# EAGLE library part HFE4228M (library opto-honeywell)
OPTO SENSOR DEVICE

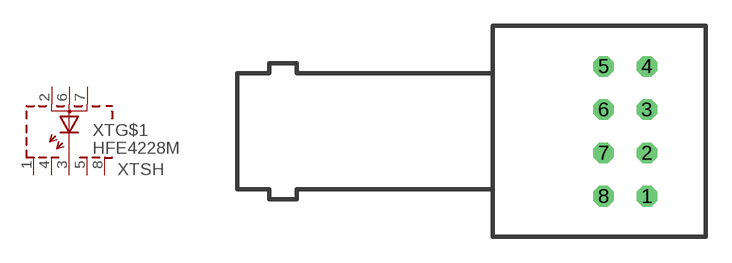
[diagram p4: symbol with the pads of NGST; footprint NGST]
Designator prefix XT; gates G$1=LED-A3 SH=CASE4COM

## HFE4228M (OC_FARNELL: unknown; OC_NEWARK: unknown)  [NGST]
1  SH:COM  pwr
2  G$1:A1  pas
3  G$1:C  pas
4  SH:COM  pwr
5  SH:COM  pwr
6  G$1:A2  pas
7  G$1:A3  pas
8  SH:COM  pwr

## Footprint NGST (pad centres in mm)
OPTO SENSOR DEVICE
drill 0.7 octagon: 1 2.54,-3.81; 2 2.54,-1.27; 3 2.54,1.27; 4 2.54,3.81; 5 0,3.81; 6 0,1.27; 7 0,-1.27; 8 0,-3.81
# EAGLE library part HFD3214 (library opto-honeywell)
OPTO SENSOR DEVICE

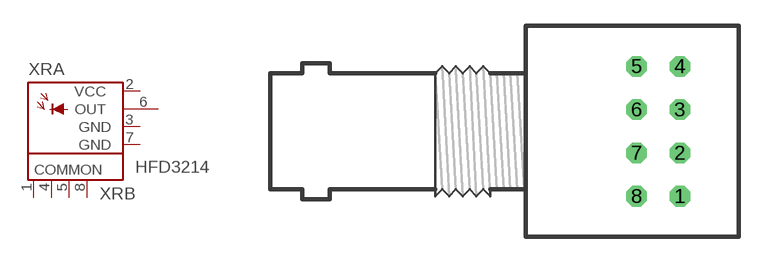
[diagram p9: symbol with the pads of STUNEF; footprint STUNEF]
Designator prefix XR; gates A=DETECT2G B=COMMON4

## HFD3214 (OC_FARNELL: unknown; OC_NEWARK: unknown)  [STUNEF]
1  B:COM  pwr
2  A:VCC  pwr
3  A:GND  pwr
4  B:COM  pwr
5  B:COM  pwr
6  A:OUT  out
7  A:GND  pwr
8  B:COM  pwr

## Footprint STUNEF (pad centres in mm)
OPTO SENSOR DEVICE
drill 0.7 octagon: 1 2.54,-3.81; 2 2.54,-1.27; 3 2.54,1.27; 4 2.54,3.81; 5 0,3.81; 6 0,1.27; 7 0,-1.27; 8 0,-3.81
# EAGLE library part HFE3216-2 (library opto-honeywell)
OPTO SENSOR DEVICE

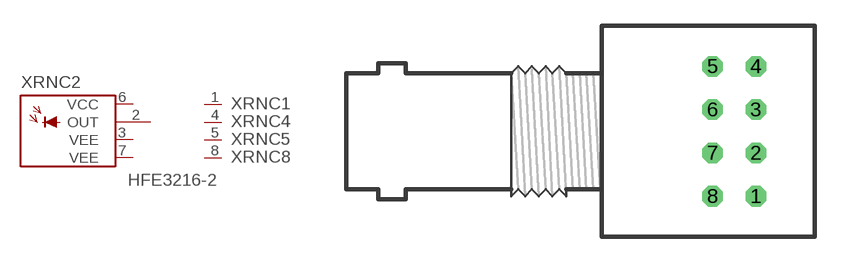
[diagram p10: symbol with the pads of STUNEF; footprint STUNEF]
Designator prefix XR; gates NC1=NC NC4=NC NC5=NC NC8=NC NC2=DET-CCEE

## HFE3216-2 (OC_FARNELL: unknown; OC_NEWARK: unknown)  [STUNEF]
1  NC1:NC  nc
2  NC2:OUT  out
3  NC2:VEE  pwr
4  NC4:NC  nc
5  NC5:NC  nc
6  NC2:VCC  pwr
7  NC2:VEE  pwr
8  NC8:NC  nc

## Footprint STUNEF (pad centres in mm)
OPTO SENSOR DEVICE
drill 0.7 octagon: 1 2.54,-3.81; 2 2.54,-1.27; 3 2.54,1.27; 4 2.54,3.81; 5 0,3.81; 6 0,1.27; 7 0,-1.27; 8 0,-3.81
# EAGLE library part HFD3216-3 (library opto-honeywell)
OPTO SENSOR DEVICE

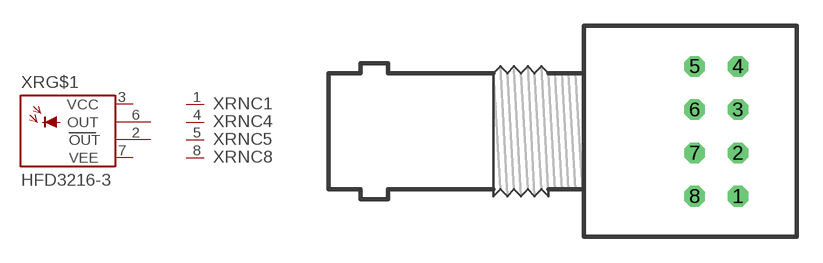
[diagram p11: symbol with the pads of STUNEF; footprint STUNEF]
Designator prefix XR; gates G$1=DETNCCEE NC1=NC NC4=NC NC5=NC NC8=NC

## HFD3216-3 (OC_FARNELL: unknown; OC_NEWARK: unknown)  [STUNEF]
1  NC1:NC  nc
2  G$1:!OUT  out
3  G$1:VCC  pwr
4  NC4:NC  nc
5  NC5:NC  nc
6  G$1:OUT  out
7  G$1:VEE  pwr
8  NC8:NC  nc

## Footprint STUNEF (pad centres in mm)
OPTO SENSOR DEVICE
drill 0.7 octagon: 1 2.54,-3.81; 2 2.54,-1.27; 3 2.54,1.27; 4 2.54,3.81; 5 0,3.81; 6 0,1.27; 7 0,-1.27; 8 0,-3.81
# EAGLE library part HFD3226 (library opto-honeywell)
OPTO SENSOR DEVICE

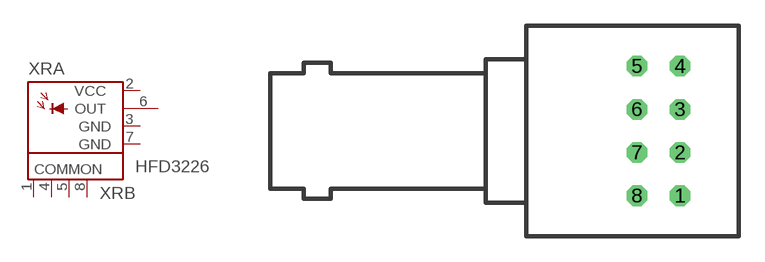
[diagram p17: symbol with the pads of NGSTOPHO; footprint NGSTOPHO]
Designator prefix XR; gates A=DETECT2G B=COMMON4

## HFD3226 (OC_FARNELL: unknown; OC_NEWARK: unknown)  [NGSTOPHO]
1  B:COM  pwr
2  A:VCC  pwr
3  A:GND  pwr
4  B:COM  pwr
5  B:COM  pwr
6  A:OUT  out
7  A:GND  pwr
8  B:COM  pwr

## Footprint NGSTOPHO (pad centres in mm)
OPTO SENSOR DEVICE
drill 0.7 octagon: 1 2.54,-3.81; 2 2.54,-1.27; 3 2.54,1.27; 4 2.54,3.81; 5 0,3.81; 6 0,1.27; 7 0,-1.27; 8 0,-3.81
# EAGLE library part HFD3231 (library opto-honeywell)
OPTO SENSOR DEVICE

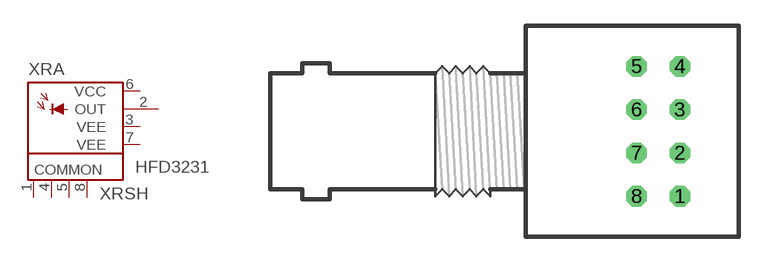
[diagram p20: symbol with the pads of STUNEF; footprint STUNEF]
Designator prefix XR; gates A=DET-CCEE SH=COMMON4

## HFD3231 (OC_FARNELL: unknown; OC_NEWARK: unknown)  [STUNEF]
1  SH:COM  pwr
2  A:OUT  out
3  A:VEE  pwr
4  SH:COM  pwr
5  SH:COM  pwr
6  A:VCC  pwr
7  A:VEE  pwr
8  SH:COM  pwr

## Footprint STUNEF (pad centres in mm)
OPTO SENSOR DEVICE
drill 0.7 octagon: 1 2.54,-3.81; 2 2.54,-1.27; 3 2.54,1.27; 4 2.54,3.81; 5 0,3.81; 6 0,1.27; 7 0,-1.27; 8 0,-3.81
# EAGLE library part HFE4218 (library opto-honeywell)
OPTO SENSOR DEVICE

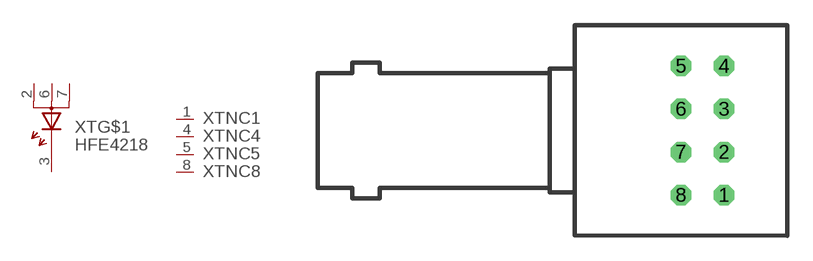
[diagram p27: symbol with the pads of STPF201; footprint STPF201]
Designator prefix XT; gates NC1=NC NC4=NC NC5=NC NC8=NC G$1=LED-A3

## HFE4218 (OC_FARNELL: unknown; OC_NEWARK: unknown)  [STPF201]
1  NC1:NC  nc
2  G$1:A1  pas
3  G$1:C  pas
4  NC4:NC  nc
5  NC5:NC  nc
6  G$1:A2  pas
7  G$1:A3  pas
8  NC8:NC  nc

## Footprint STPF201 (pad centres in mm)
OPTO SENSOR DEVICE
drill 0.7 octagon: 1 2.54,-3.81; 2 2.54,-1.27; 3 2.54,1.27; 4 2.54,3.81; 5 0,3.81; 6 0,1.27; 7 0,-1.27; 8 0,-3.81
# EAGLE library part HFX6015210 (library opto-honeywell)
OPTO SENSOR DEVICE

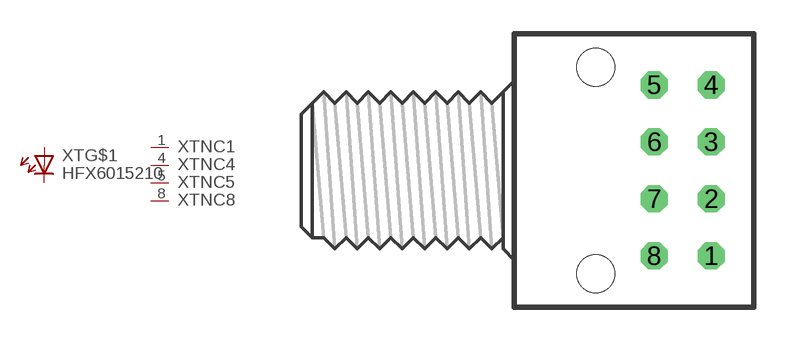
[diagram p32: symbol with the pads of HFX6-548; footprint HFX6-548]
Designator prefix XT; gates G$1=LED NC1=NC NC4=NC NC5=NC NC8=NC

## HFX6015210 (OC_FARNELL: unknown; OC_NEWARK: unknown)  [HFX6-548]
1  NC1:NC  nc
2  G$1:A  pas
3  G$1:C  pas
4  NC4:NC  nc
5  NC5:NC  nc
8  NC8:NC  nc

## Footprint HFX6-548 (pad centres in mm)
OPTO SENSOR DEVICE
drill 0.7 octagon: 1 1.27,-3.81; 2 1.27,-1.27; 3 1.27,1.27; 4 1.27,3.81; 5 -1.27,3.81; 6 -1.27,1.27; 7 -1.27,-1.27; 8 -1.27,-3.81
hole 1.7 at -3.87,-4.6
hole 1.7 at -3.87,4.6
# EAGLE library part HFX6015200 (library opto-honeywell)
OPTO SENSOR DEVICE

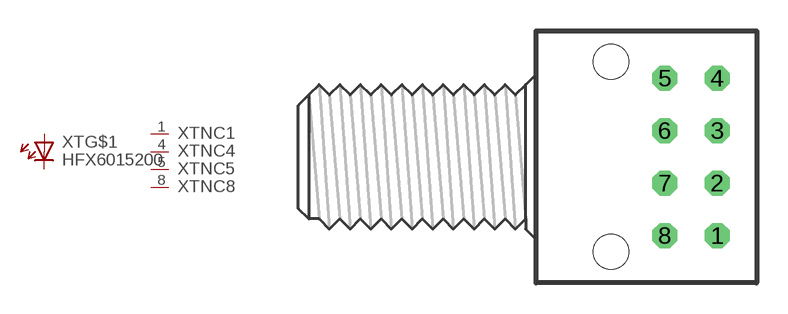
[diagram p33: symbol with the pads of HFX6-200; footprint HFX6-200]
Designator prefix XT; gates NC1=NC NC4=NC NC5=NC NC8=NC G$1=LED

## HFX6015200 (MPN: HFX6015-200; OC_FARNELL: unknown; OC_NEWARK: 34M4550)  [HFX6-200]
1  NC1:NC  nc
2  G$1:A  pas
3  G$1:C  pas
4  NC4:NC  nc
5  NC5:NC  nc
8  NC8:NC  nc

## Footprint HFX6-200 (pad centres in mm)
OPTO SENSOR DEVICE
drill 0.7 octagon: 1 1.27,-3.81; 2 1.27,-1.27; 3 1.27,1.27; 4 1.27,3.81; 5 -1.27,3.81; 6 -1.27,1.27; 7 -1.27,-1.27; 8 -1.27,-3.81
hole 1.7 at -3.87,-4.6
hole 1.7 at -3.87,4.6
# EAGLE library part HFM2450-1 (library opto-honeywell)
OPTO SENSOR DEVICE

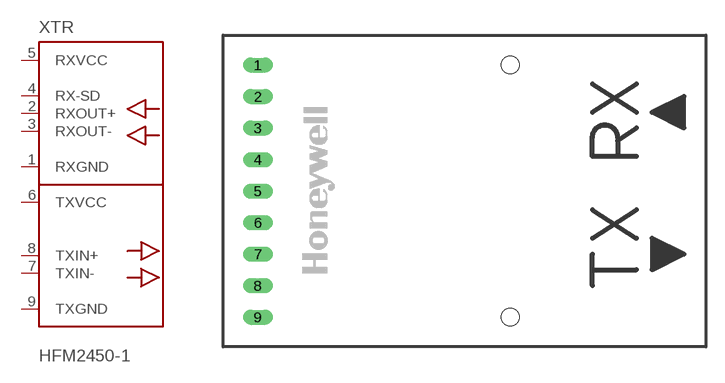
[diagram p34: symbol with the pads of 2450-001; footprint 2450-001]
Designator prefix XTR

## HFM2450-1 (OC_FARNELL: unknown; OC_NEWARK: unknown)  [2450-001]
1  RXGND  pwr
2  RXOUT+  out
3  RXOUT-  out
4  RX-SD  out
5  RXVCC  out
6  TXVCC  out
7  TXIN-  out
8  TXIN+  out
9  TXGND  pwr

## Footprint 2450-001 (pad centres in mm)
OPTO SENSOR DEVICE
drill 0.7 long: 1 -15.24,10.16; 2 -15.24,7.62; 3 -15.24,5.08; 4 -15.24,2.54; 5 -15.24,0; 6 -15.24,-2.54; 7 -15.24,-5.08; 8 -15.24,-7.62; 9 -15.24,-10.16
hole 1.422 at 5.08,10.16
hole 1.422 at 5.08,-10.16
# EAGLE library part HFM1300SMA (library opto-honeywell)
OPTO SENSOR DEVICE

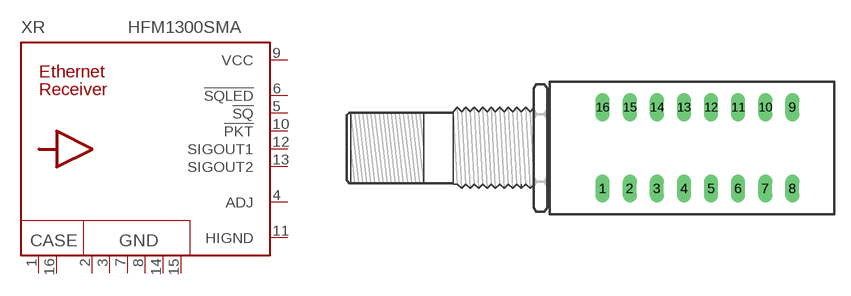
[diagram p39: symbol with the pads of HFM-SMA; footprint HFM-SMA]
Designator prefix XR

## HFM1300SMA (OC_FARNELL: unknown; OC_NEWARK: unknown)  [HFM-SMA]
1  CASEGND  pwr
2  GND  pwr
3  GND  pwr
4  ADJ  in
5  !SQ  out
6  !SQLED  out
7  GND  pwr
8  GND  pwr
9  VCC  pwr
10  !PKT  out
11  HIGND  pwr
12  SIGOUT1  out
13  SIGOUT2  out
14  GND  pwr
15  GND  pwr
16  CASEGND  pwr

## Footprint HFM-SMA (pad centres in mm)
OPTO SENSOR DEVICE
drill 0.813 long: 1 -8.89,-3.81; 2 -6.35,-3.81; 3 -3.81,-3.81; 4 -1.27,-3.81; 5 1.27,-3.81; 6 3.81,-3.81; 7 6.35,-3.81; 8 8.89,-3.81; 9 8.89,3.81; 10 6.35,3.81; 11 3.81,3.81; 12 1.27,3.81; 13 -1.27,3.81; 14 -3.81,3.81; 15 -6.35,3.81; 16 -8.89,3.81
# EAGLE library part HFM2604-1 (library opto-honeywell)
OPTO SENSOR DEVICE

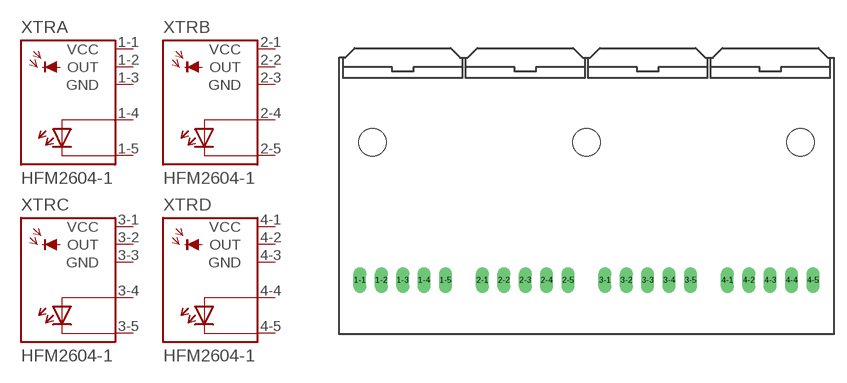
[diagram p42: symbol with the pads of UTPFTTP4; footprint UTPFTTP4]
Designator prefix XTR; gates A=RX-LED B=RX-LED C=RX-LED D=RX-LED

## HFM2604-1 (OC_FARNELL: unknown; OC_NEWARK: unknown)  [UTPFTTP4]
1-1  A:VCC  pwr
1-2  A:OUT  out
1-3  A:GND  pwr
1-4  A:A  pas
1-5  A:C  pas
2-1  B:VCC  pwr
2-2  B:OUT  out
2-3  B:GND  pwr
2-4  B:A  pas
2-5  B:C  pas
3-1  C:VCC  pwr
3-2  C:OUT  out
3-3  C:GND  pwr
3-4  C:A  pas
3-5  C:C  pas
4-1  D:VCC  pwr
4-2  D:OUT  out
4-3  D:GND  pwr
4-4  D:A  pas
4-5  D:C  pas

## Footprint UTPFTTP4 (pad centres in mm)
OPTO SENSOR DEVICE
drill 1.016 long: 1-1 -26.873,0; 1-2 -24.333,0; 1-3 -21.793,0; 1-4 -19.253,0; 1-5 -16.713,0; 2-1 -12.344,0; 2-2 -9.804,0; 2-3 -7.264,0; 2-4 -4.724,0; 2-5 -2.184,0; 3-1 2.184,0; 3-2 4.724,0; 3-3 7.264,0; 3-4 9.804,0; 3-5 12.344,0; 4-1 16.713,0; 4-2 19.253,0; 4-3 21.793,0; 4-4 24.333,0; 4-5 26.873,0
hole 3.277 at -25.4,16.358
hole 3.277 at 0,16.358
hole 3.277 at 25.4,16.358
